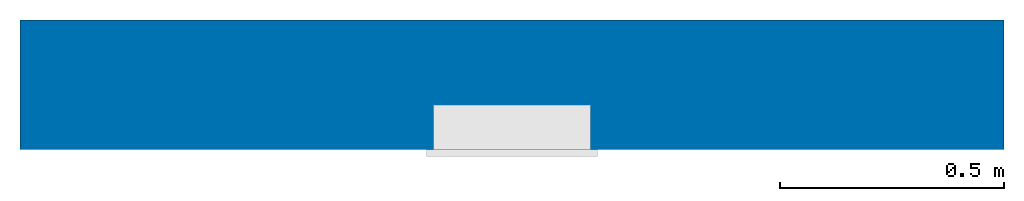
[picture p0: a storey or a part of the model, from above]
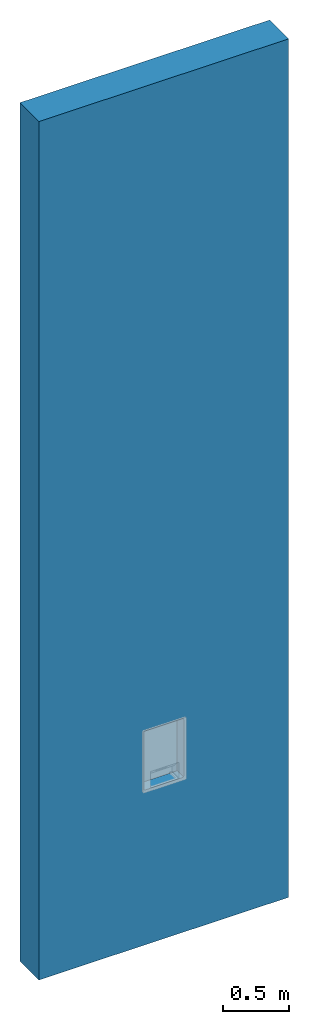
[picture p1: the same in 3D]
Properties of the parts of a building model (IFC2X3)

# File
Description: ViewDefinition [CoordinationView]
File name: Project Number
Time: 2019-05-16T18:01:26
Written by: The EXPRESS Data Manager Version 5.02.0100.07 : 28 Aug 2013
Made in: 20140606_1530(x64) - Exporter 2015.0.2014.0606 - Default UI
Comment: STEP Physical File produced by: The EXPRESS Data Manager Version 5.02.0100.07 : 28 Aug 2013 * Module: EDMstepFileFactory/EDMstandAlone * Creation date: Thu May 16 18:01:26 2019 * Host: SarahSams-HP * Database: C:\Users\SARAHS~1\AppData\Local\Temp\{739F5252-0610-41D8-A2CF-0676046F55A6}\ifc * Database version: 5507 * Database creation date: Thu May 16 18:01:26 2019 * Schema: IFC2X3 * Model: DataRepository.ifc * Model creation date: Thu May 16 18:01:26 2019 * Header model: DataRepository.ifc_HeaderModel * Header model creation date: Thu May 16 18:01:26 2019 * EDMuser: sdai-user * EDMgroup: sdai-group * License ID and type: 5605 : Permanent license. Expiry date: * EDMstepFileFactory options: 020000

# IfcProject, Project Number
LongName: Project Name; Phase: Project Status

# IfcSite, Default
RefLatitude: 51, 30, 0, 549316; RefLongitude: 0, -7, -34, -450321; RefElevation: 0 mm
Other - Category: Project Information; Client Name: Owner; Project Address: Enter address here; Project Issue Date: Issue Date; Project Name: Project Name; Project Number: Project Number; Project Status: Project Status

# IfcBuilding
Pset_BuildingCommon - NumberOfStoreys: 1
Other - Category: Project Information; Client Name: Owner; Project Address: Enter address here; Project Issue Date: Issue Date; Project Name: Project Name; Project Number: Project Number; Project Status: Project Status

# IfcBuildingStorey, Level 0
LongName: Level 0; Elevation: 0 mm
Other - Category: Levels; Family Name: Level; Family: Level: Circle Head - Project Datum; Family and Type: Level: Circle Head - Project Datum; Type: Level: Circle Head - Project Datum; Type Id: Level: Circle Head - Project Datum
Identity Data - Type Name: Circle Head - Project Datum; Structural: no; Building Story: yes; Name: Level 0
Graphics - Color: 0; Line Pattern: Centre; Line Weight: 1; Symbol: Anno_Level_Head_Circle: Standard; Symbol at End 1 Default: yes; Symbol at End 2 Default: no
Constraints - Elevation: 0 mm; Elevation Base: Project Base Point
Dimensions - Computation Height: 0 mm

# IfcBuildingElementProxy: High Speed Hand Dryer, Duten_HndDriers_M440:High Speed Hand Dryer:288393
In: Level 0
Classification: E2020200 Furniture & Accessories (Uniformat); Material: Duten_Metal_BrushedStainlessSteel
Pset_BuildingElementProxyCommon - Reference: n/a
Pset_ManufacturerTypeInformation - ModelReference: High speed forced air hand dryer for recessed installation; Manufacturer: Duten
Constraints - Level: Level: Level 0; Elevation: 1717.31 mm; Host: Basic Wall : Wall-Ext_102Bwk-75Ins-100LBlk-12P; Default Elevation: 1200 mm
Dimensions - Area: 0.54465 m2; Volume: 0.0184193 m3
Other - Category: Generic Models; Family: Duten_HndDriers_M440: High Speed Hand Dryer; Family and Type: Duten_HndDriers_M440: High Speed Hand Dryer; Schedule Level: Level: Level 0; Type: Duten_HndDriers_M440: High Speed Hand Dryer; Type Id: Duten_HndDriers_M440: High Speed Hand Dryer; AccessibilityPerformance: n/a; AssetIdentifier: n/a; AssetType: Moveable; BarCode: n/a; CodePerformance: Certifications: CE, IP21; Color: Defined by Finish; Constituents: Stainless steel AISI 304; DurationUnit: Years; ExpectedLife: 5; Family Name: Duten_HndDriers_M440; Features: 2600W forced air hand dryer for installation in the wall. 100mm embedment depth which allows installation in narrow cavities. 220-240V power supply. Frequency 50 / 60Hz. This hand dryer can be installed in combination with the E040-S paper towel dispenser and / or the P740-S waste bin.; Finish: Stainless steel AISI 304; Grade: n/a; InstallationDate: 1900-12-31T23:59:59; Material: Stainless steel AISI 304; ModelNumber: E050; ModelReference: High speed forced air hand dryer for recessed installation; Name: HandDriers_M440_Duten; ReplacementCost: 0; SerialNumber: n/a; Shape: Rectangular; Size: (H) 579mm x (L) 116mm x (W) 382mm; SustainabilityPerformance: n/a; TagNumber: n/a; WarrantyDescription: n/a; WarrantyDurationLabor: 5; WarrantyDurationParts: 5; WarrantyDurationUnit: Years; WarrantyGuarantorLabor: contact@duten.fr; WarrantyGuarantorParts: contact@duten.fr; WarrantyStartDate: 1900-12-31T23:59:59
Phasing - Phase Created: New Construction
General - Author: Diane Butterworth Ltd; ManufacturerName: Duten; ManufacturerURL: http://www.duten.fr/; NBSDescription: Paper Towel Dispensers; NBSReference: 45-35-72/344; ProductInformation: www.duten.fr/produit/seche-mains-encastre-m440; Revision: n/a; Uniclass2015Code: Pr-Products v1.10; Uniclass2015Title: Hand Driers; Uniclass2015Version: Pr_40_70_62_37
Identity Data - Assembly Code: E2020200; Assembly Description: Furniture & Accessories; Cost: 0; Description: High speed forced air hand dryer for recessed installation; Keynote: Pr_40_70_62_37; Manufacturer: Duten; Model: E050; Type Comments: High speed forced air hand dryer for recessed installation; Type Name: High Speed Hand Dryer; URL: http://www.duten.fr/

# IfcOpeningElement: Recess, Basic Wall:Wall-Ext_102Bwk-75Ins-100LBlk-12P:285312
In: Level 0
Constraints - Elevation: 1717.31 mm; Host: Basic Wall : Wall-Ext_102Bwk-75Ins-100LBlk-12P; Level: Level: Level 0; Default Elevation: 1200 mm
Dimensions - Area: 0.54465 m2; Volume: 0.0184193 m3
Other - Category: Generic Models; Family: Duten_HndDriers_M440: High Speed Hand Dryer; Family and Type: Duten_HndDriers_M440: High Speed Hand Dryer; Schedule Level: Level: Level 0; Type: Duten_HndDriers_M440: High Speed Hand Dryer; Type Id: Duten_HndDriers_M440: High Speed Hand Dryer; AccessibilityPerformance: n/a; AssetIdentifier: n/a; AssetType: Moveable; BarCode: n/a; CodePerformance: Certifications: CE, IP21; Color: Defined by Finish; Constituents: Stainless steel AISI 304; DurationUnit: Years; ExpectedLife: 5; Family Name: Duten_HndDriers_M440; Features: 2600W forced air hand dryer for installation in the wall. 100mm embedment depth which allows installation in narrow cavities. 220-240V power supply. Frequency 50 / 60Hz. This hand dryer can be installed in combination with the E040-S paper towel dispenser and / or the P740-S waste bin.; Finish: Stainless steel AISI 304; Grade: n/a; InstallationDate: 1900-12-31T23:59:59; Material: Stainless steel AISI 304; ModelNumber: E050; ModelReference: High speed forced air hand dryer for recessed installation; Name: HandDriers_M440_Duten; ReplacementCost: 0; SerialNumber: n/a; Shape: Rectangular; Size: (H) 579mm x (L) 116mm x (W) 382mm; SustainabilityPerformance: n/a; TagNumber: n/a; WarrantyDescription: n/a; WarrantyDurationLabor: 5; WarrantyDurationParts: 5; WarrantyDurationUnit: Years; WarrantyGuarantorLabor: contact@duten.fr; WarrantyGuarantorParts: contact@duten.fr; WarrantyStartDate: 1900-12-31T23:59:59
Phasing - Phase Created: New Construction
General - Author: Diane Butterworth Ltd; ManufacturerName: Duten; ManufacturerURL: http://www.duten.fr/; NBSDescription: Paper Towel Dispensers; NBSReference: 45-35-72/344; ProductInformation: www.duten.fr/produit/seche-mains-encastre-m440; Revision: n/a; Uniclass2015Code: Pr-Products v1.10; Uniclass2015Title: Hand Driers; Uniclass2015Version: Pr_40_70_62_37
Identity Data - Assembly Code: E2020200; Assembly Description: Furniture & Accessories; Cost: 0; Description: High speed forced air hand dryer for recessed installation; Keynote: Pr_40_70_62_37; Manufacturer: Duten; Model: E050; Type Comments: High speed forced air hand dryer for recessed installation; Type Name: High Speed Hand Dryer; URL: http://www.duten.fr/

# IfcWallStandardCase: Basic Wall:Wall-Ext_102Bwk-75Ins-100LBlk-12P, Basic Wall:Wall-Ext_102Bwk-75Ins-100LBlk-12P:285312
In: Level 0
Type - PredefinedType: STANDARD; Material: Brick, Common 102.5 mm, Fiberglass Batt 75 mm, Concrete Masonry Units _Low Density 100 mm, Plaster 12.5 mm
Type - Analytical Properties - Absorptance: 0.7; Heat Transfer Coefficient (U): 0.235926; Roughness: 3; Thermal mass: 300303; Thermal Resistance (R): 4.23862
Type - Construction - Function: Exterior; Width: 290 mm; Wrapping at Inserts: Both
Type - Graphics - Coarse Scale Fill Color: 12632256; Coarse Scale Fill Pattern: Solid fill
Type - Identity Data - Keynote: F10; Type Name: Wall-Ext_102Bwk-75Ins-100LBlk-12P
Type - Materials and Finishes - Structural Material: Concrete Masonry Units _Low Density
Type - Other - Category: Walls; Family Name: Basic Wall
Constraints - Base Constraint: Level: Level 0; Base Extension Distance: 0 mm; Base is Attached: no; Base Offset: 0 mm; Location Line: Wall Centerline; Related to Mass: no; Room Bounding: yes; Top Extension Distance: 0 mm; Top is Attached: no; Top Offset: 0 mm; Unconnected Height: 8000 mm
Dimensions - Area: 17.6 m2; Length: 2200 mm; Volume: 5.08468 m3
Other - Family: Basic Wall: Wall-Ext_102Bwk-75Ins-100LBlk-12P; Family and Type: Basic Wall: Wall-Ext_102Bwk-75Ins-100LBlk-12P; Type: Basic Wall: Wall-Ext_102Bwk-75Ins-100LBlk-12P; Type Id: Basic Wall: Wall-Ext_102Bwk-75Ins-100LBlk-12P
Phasing - Phase Created: New Construction
Structural - Enable Analytical Model: no; Structural: no; Structural Usage: Non-bearing
Pset_WallCommon - Reference: Wall-Ext_102Bwk-75Ins-100LBlk-12P; LoadBearing: no; ExtendToStructure: no; IsExternal: yes; ThermalTransmittance: 0.235926 kg/K/s3
